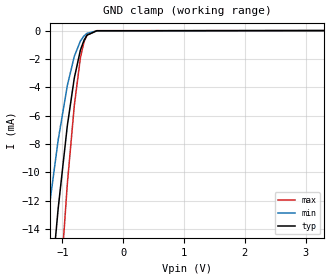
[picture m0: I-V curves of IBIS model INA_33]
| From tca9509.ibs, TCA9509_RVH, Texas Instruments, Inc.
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[Model]   INA_33
Model_type  Input
Vinl=0.15
Vinh=2.31
| variable   typ   min   max
C_comp   1.60pF   1.25pF   1.83pF
[Temperature Range]   40   100   -40
| Ambient temperature   25   85   -40
[Voltage range]   3.3   3   3.6
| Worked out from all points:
|   GND clamp passes 1 mA (typ) near -0.68 V on its own axis
[GND Clamp]
| INA_33
|   Voltage   I(typ)   I(min)   I(max)
-3.3V     -179.4mA   -131.1mA   -253.4mA
-1.42V    -30.67mA   -20.24mA   -47.89mA
-1.4V     -29.5mA    -19.42mA   -46.12mA
-1.22V    -19.63mA   -12.55mA   -31.1mA
-1.07V    -12.54mA   -7.714mA   -20.08mA
-920mV    -6.722mA   -3.883mA   -10.84mA
-805mV    -3.354mA   -1.825mA   -5.303mA
-705mV    -1.39mA    -740.7uA   -1.939mA
-645mV    -679uA     -375.8uA   -797.3uA
-595mV    -324.9uA   -196.1uA   -314.7uA
-435mV    -15.07uA   -14.81uA   -6.498uA
3.3V      311.6pA    1.532nA    54.55pA
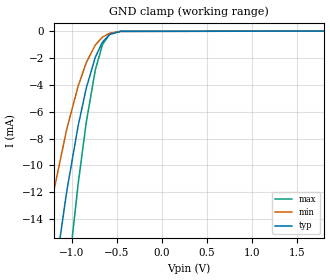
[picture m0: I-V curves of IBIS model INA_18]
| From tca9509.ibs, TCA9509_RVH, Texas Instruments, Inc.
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[Model]   INA_18
Model_type  Input
Vinl=0.15
Vinh=1.26
| variable   typ   min   max
C_comp   1.61pF   1.15pF   1.86pF
[Temperature Range]   40   100   -40
| Ambient temperature   25   85   -40
[Voltage range]   1.8   1.65   1.95
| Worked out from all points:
|   GND clamp passes 1 mA (typ) near -0.68 V on its own axis
[GND Clamp]
| INA_18
|   Voltage   I(typ)   I(min)   I(max)
-1.8V     -55.53mA   -37.93mA   -84.39mA
-1.395V   -29.2mA    -19.21mA   -45.68mA
-1.215V   -19.37mA   -12.38mA   -30.7mA
-1.065V   -12.32mA   -7.569mA   -19.74mA
-1.05V    -11.68mA   -7.139mA   -18.73mA
-930mV    -7.063mA   -4.101mA   -11.39mA
-840mV    -4.263mA   -2.36mA    -6.822mA
-740mV    -1.966mA   -1.047mA   -2.926mA
-660mV    -825.4uA   -449.9uA   -1.019mA
-580mV    -253.7uA   -159uA     -230.8uA
-460mV    -25.6uA    -23.29uA   -12.99uA
1.8V      196.2pA    1.052nA    29.84pA
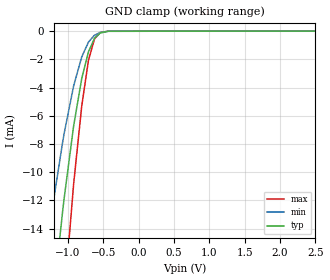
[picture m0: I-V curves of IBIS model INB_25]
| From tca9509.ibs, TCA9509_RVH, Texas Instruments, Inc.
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[Model]   INB_25
Model_type  Input
Vinl=0.15
Vinh=1.75
| variable   typ   min   max
C_comp   1.62pF   1.21pF   1.89pF
[Temperature Range]   40   100   -40
| Ambient temperature   25   85   -40
[Voltage range]   2.5   2.3   2.7
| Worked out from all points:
|   GND clamp passes 1 mA (typ) near -0.68 V on its own axis
[GND Clamp]
| INB_25
|   Voltage   I(typ)   I(min)   I(max)
-2.5V     -109.9mA   -78.03mA   -160.4mA
-1.405V   -29.79mA   -19.62mA   -46.56mA
-1.21V    -19.12mA   -12.2mA    -30.31mA
-1.075V   -12.75mA   -7.861mA   -20.42mA
-1.055V   -11.89mA   -7.281mA   -19.07mA
-920mV    -6.722mA   -3.883mA   -10.84mA
-805mV    -3.354mA   -1.825mA   -5.303mA
-710mV    -1.465mA   -779.9uA   -2.066mA
-625mV    -513.9uA   -292.4uA   -560.9uA
-545mV    -136.8uA   -94.94uA   -106.9uA
-430mV    -13.52uA   -13.5uA    -5.631uA
2.5V      247.4pA    1.266nA    41.34pA
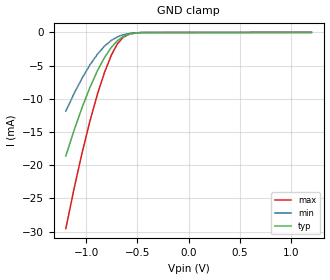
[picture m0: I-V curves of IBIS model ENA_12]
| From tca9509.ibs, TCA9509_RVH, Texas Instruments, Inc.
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[Model]   ENA_12
Model_type  Input
Vinl=0.15
Vinh=0.84
| variable   typ   min   max
C_comp   1.62pF   1.12pF   1.86pF
[Temperature Range]   40   100   -40
| Ambient temperature   25   85   -40
[Voltage range]   1.2   1.1   1.3
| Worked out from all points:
|   GND clamp passes 1 mA (typ) near -0.68 V on its own axis
[GND Clamp]
| ENA_12
|   Voltage   I(typ)   I(min)   I(max)
-1.2V     -18.61mA   -11.86mA   -29.54mA
-1.12V    -14.77mA   -9.228mA   -23.57mA
-1.04V    -11.26mA   -6.859mA   -18.07mA
-965mV    -8.314mA   -4.909mA   -13.39mA
-890mV    -5.741mA   -3.265mA   -9.247mA
-820mV    -3.73mA    -2.044mA   -5.935mA
-755mV    -2.25mA    -1.202mA   -3.417mA
-695mV    -1.248mA   -666.5uA   -1.7mA
-640mV    -634.6uA   -353.3uA   -732.1uA
-570mV    -213.8uA   -137.7uA   -186.4uA
-465mV    -28.41uA   -25.44uA   -14.85uA
1.2V      155.6pA    881.8pA    20.05pA
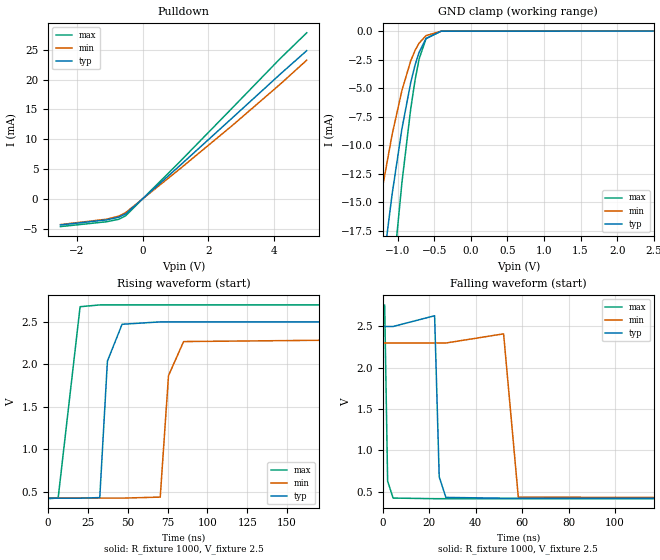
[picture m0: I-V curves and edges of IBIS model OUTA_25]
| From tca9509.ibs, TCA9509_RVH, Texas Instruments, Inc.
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[Model]   OUTA_25
Model_type  Open_drain
Enable   Active-High
Vref =   2.5
Rref =   1350
Cref =   50p
Vmeas =   1.25
| variable   typ   min   max
C_comp   2.30pF   1.66pF   2.63pF
| C_pulldown   1.52pF   1.14pF   1.79pF
| C_tri-state   2.30pF   1.66pF   2.63pF
[Temperature Range]   40   100   -40
| Ambient temperature   25   85   -40
[Voltage range]   2.5   2.3   2.7
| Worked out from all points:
|   slope of the pulldown table from 0 to 0.375 V, typ, clamps not added: 203 ohm
|   GND clamp passes 1 mA (typ) near -0.64 V on its own axis
|   rising waveform, R_fixture 1000, V_fixture 2.5: 20-80 % time 4.21ns typ, 4.62ns min, 3.89ns max; typ from 0.421 V to 2.5 V
|   falling waveform, R_fixture 1000, V_fixture 2.5: 20-80 % time 1.05ns typ, 1.56ns min, 682ps max; typ from 2.5 V to 0.421 V
[GND Clamp]
| OUTA_25
|   Voltage   I(typ)   I(min)   I(max)
-2.5V     -116.5mA   -83.67mA   -168.1mA
-1.425V   -33.77mA   -22.73mA   -51.61mA
-1.41V    -32.83mA   -22.07mA   -50.22mA
-1.225V   -21.99mA   -14.42mA   -33.96mA
-1.075V   -14.36mA   -9.116mA   -22.29mA
-940mV    -8.582mA   -5.209mA   -13.3mA
-820mV    -4.53mA    -2.622mA   -6.844mA
-760mV    -2.975mA   -1.694mA   -4.287mA
-705mV    -1.863mA   -1.062mA   -2.452mA
-610mV    -653.2uA   -398.9uA   -659.5uA
-405mV    -18.62uA   -19.65uA   -6.563uA
2.5V      643.1pA    3.147nA    138.3pA
[Pulldown]
| OUTA_25
|   Voltage   I(typ)   I(min)   I(max)
-2.5V     -4.294mA   -4.237mA   -4.572mA
-1.085V   -3.445mA   -3.33mA    -3.755mA
-720mV    -2.99mA    -2.815mA   -3.343mA
-515mV    -2.46mA    -2.232mA   -2.772mA
1.13V     5.587mA    5.039mA    6.233mA
2.73V     13.57mA    12.3mA     15.23mA
4.19V     20.88mA    19.21mA    23.49mA
5V        24.82mA    23.23mA    27.8mA
[Ramp]
| OUTA_25
| variable   typ   min   max
dV/dt_r   1.25/4.20E-09   1.13/4.60E-09   1.37/3.88E-09
dV/dt_f   1.32/1.11E-09   1.19/1.66E-09   1.46/7.19E-10
R_load = 1000
[Rising Waveform]
| OUTA_25
R_fixture =   1000
C_fixture =   0
L_fixture =   0
V_fixture =   2.5
V_fixture_min = 2.3
V_fixture_max = 2.7
|   Time   V(typ)   V(min)   V(max)
0s        421mV      421.9mV    415.3mV
6.277ns   421mV      421.9mV    423.7mV
20.04ns   421mV      421.9mV    2.679V
32.39ns   428.4mV    421.9mV    2.7V
37.19ns   2.038V     421.9mV    2.7V
46.4ns    2.472V     421.9mV    2.7V
70.34ns   2.5V       434.1mV    2.7V
75.53ns   2.5V       1.866V     2.7V
85ns      2.5V       2.268V     2.7V
266.4ns   2.5V       2.3V       2.7V
[Falling Waveform]
| OUTA_25
R_fixture =   1000
C_fixture =   0
L_fixture =   0
V_fixture =   2.5
V_fixture_min = 2.3
V_fixture_max = 2.7
|   Time   V(typ)   V(min)   V(max)
0s        2.5V       2.3V       2.7V
773ps     2.5V       2.3V       2.761V
2.053ns   2.5V       2.3V       627mV
4.421ns   2.5V       2.3V       422.9mV
22.28ns   2.63V      2.3V       415.5mV
24.26ns   678.8mV    2.3V       415.5mV
27.14ns   431mV      2.3V       415.5mV
51.98ns   421.1mV    2.411V     415.4mV
58.31ns   421.1mV    434.1mV    415.4mV
266.4ns   421mV      421.9mV    415.4mV
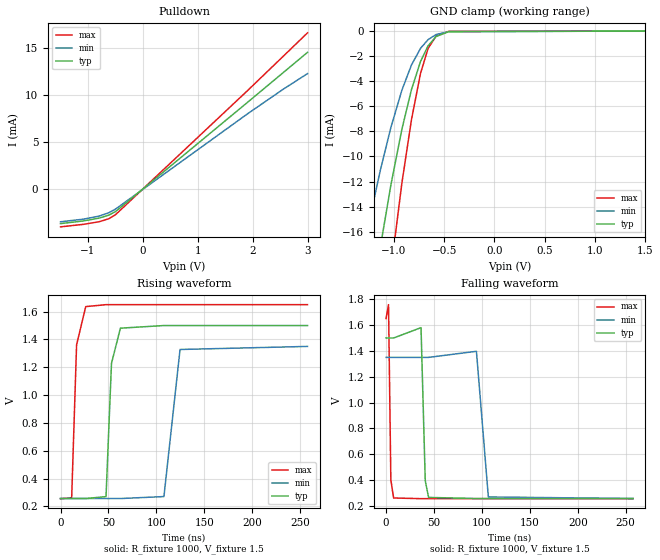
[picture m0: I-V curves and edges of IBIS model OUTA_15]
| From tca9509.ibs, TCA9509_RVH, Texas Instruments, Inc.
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[Model]   OUTA_15
Model_type  Open_drain
Enable   Active-High
Vref =   1.5
Rref =   1350
Cref =   50p
Vmeas =   0.75
| variable   typ   min   max
C_comp   2.24pF   1.55pF   2.59pF
| C_pulldown   1.49pF   1.04pF   1.72pF
| C_tri-state   2.24pF   1.55pF   2.59pF
[Temperature Range]   40   100   -40
| Ambient temperature   25   85   -40
[Voltage range]   1.5   1.35   1.65
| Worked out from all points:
|   slope of the pulldown table from 0 to 0.225 V, typ, clamps not added: 207 ohm
|   GND clamp passes 1 mA (typ) near -0.64 V on its own axis
|   rising waveform, R_fixture 1000, V_fixture 1.5: 20-80 % time 4.8ns typ, 5.8ns min, 4.18ns max; typ from 0.257 V to 1.5 V
|   falling waveform, R_fixture 1000, V_fixture 1.5: 20-80 % time 2.31ns typ, 4.22ns min, 1.3ns max; typ from 1.5 V to 0.257 V
[GND Clamp]
| OUTA_15
|   Voltage   I(typ)   I(min)   I(max)
-1.5V     -38.59mA   -26.17mA   -58.73mA
-1.37V    -30.37mA   -20.32mA   -46.55mA
-1.25V    -23.37mA   -15.38mA   -36.05mA
-1.135V   -17.27mA   -11.13mA   -26.77mA
-1.03V    -12.31mA   -7.711mA   -19.12mA
-920mV    -7.829mA   -4.714mA   -12.12mA
-825mV    -4.675mA   -2.71mA    -7.079mA
-735mV    -2.432mA   -1.382mA   -3.384mA
-660mV    -1.183mA   -687.3uA   -1.393mA
-580mV    -435.1uA   -278.8uA   -396.9uA
-455mV    -52.59uA   -46.76uA   -26.73uA
1.5V      453pA      2.396nA    83.27pA
[Pulldown]
| OUTA_15
|   Voltage   I(typ)   I(min)   I(max)
-1.5V     -3.612mA   -3.422mA   -3.956mA
-1.08V    -3.33mA    -3.14mA    -3.689mA
-795mV    -3.03mA    -2.816mA   -3.412mA
-620mV    -2.716mA   -2.462mA   -3.097mA
-495mV    -2.332mA   -2.067mA   -2.655mA
1.905V    9.201mA    7.988mA    10.44mA
2.55V     12.32mA    10.57mA    14.04mA
3V        14.5mA     12.25mA    16.56mA
[Ramp]
| OUTA_15
| variable   typ   min   max
dV/dt_r   0.75/4.78E-09   0.66/5.78E-09   0.84/4.17E-09
dV/dt_f   0.80/2.49E-09   0.69/4.44E-09   0.91/1.42E-09
R_load = 1000
[Rising Waveform]
| OUTA_15
R_fixture =   1000
C_fixture =   0
L_fixture =   0
V_fixture =   1.5
V_fixture_min = 1.35
V_fixture_max = 1.65
|   Time   V(typ)   V(min)   V(max)
0s        257.3mV    257.1mV    256.1mV
11.65ns   257.3mV    257.1mV    262.1mV
16.77ns   257.3mV    257.1mV    1.361V
26.31ns   257.3mV    257.1mV    1.636V
47.49ns   270.8mV    257.1mV    1.65V
53.19ns   1.228V     257.1mV    1.65V
62.47ns   1.481V     257.1mV    1.65V
107.9ns   1.5V       271.3mV    1.65V
124.7ns   1.5V       1.328V     1.65V
257.7ns   1.5V       1.35V      1.65V
[Falling Waveform]
| OUTA_15
R_fixture =   1000
C_fixture =   0
L_fixture =   0
V_fixture =   1.5
V_fixture_min = 1.35
V_fixture_max = 1.65
|   Time   V(typ)   V(min)   V(max)
0s        1.5V       1.35V      1.65V
2.565ns   1.5V       1.35V      1.758V
4.997ns   1.5V       1.35V      401mV
7.877ns   1.5V       1.35V      261.5mV
36.48ns   1.58V      1.35V      256.2mV
40.9ns    394.8mV    1.35V      256.2mV
44.36ns   265.8mV    1.35V      256.2mV
94.28ns   257.3mV    1.397V     256.2mV
106.7ns   257.3mV    269.6mV    256.2mV
257.7ns   257.3mV    257.1mV    256.1mV
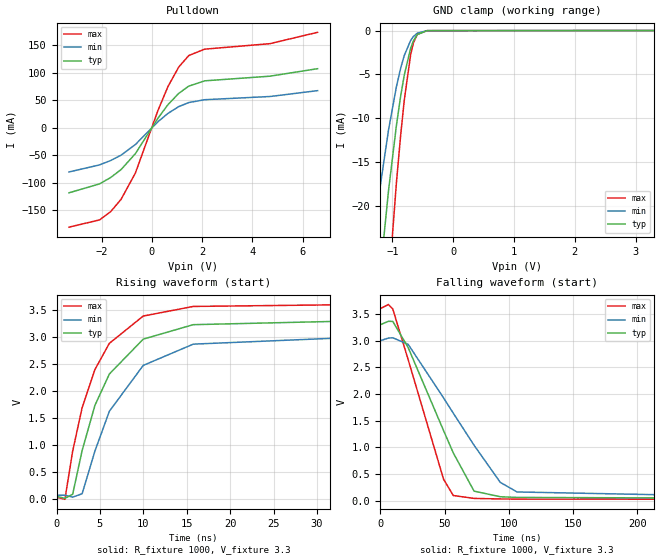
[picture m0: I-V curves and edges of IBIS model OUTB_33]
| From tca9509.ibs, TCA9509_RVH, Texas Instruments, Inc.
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[Model]   OUTB_33
Model_type  Open_drain
Enable   Active-High
Vref =   3.3
Rref =   1350
Cref =   50p
Vmeas =   1.65
| variable   typ   min   max
C_comp   2.88pF   2.03pF   3.27pF
| C_pulldown   2.79pF   2.11pF   3.88pF
| C_tri-state   2.88pF   2.03pF   3.27pF
[Temperature Range]   40   100   -40
| Ambient temperature   25   85   -40
[Voltage range]   3.3   3   3.6
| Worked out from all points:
|   slope of the pulldown table from 0 to 0.495 V, typ, clamps not added: 14.8 ohm
|   GND clamp passes 1 mA (typ) near -0.64 V on its own axis
|   rising waveform, R_fixture 1000, V_fixture 3.3: 20-80 % time 4.93ns typ, 5.55ns min, 4.4ns max; typ from 0.044 V to 3.3 V
|   falling waveform, R_fixture 1000, V_fixture 3.3: 20-80 % time 34.8ns typ, 47.4ns min, 26.1ns max; typ from 3.3 V to 0.044 V
[GND Clamp]
| OUTB_33
|   Voltage   I(typ)   I(min)   I(max)
-3.3V     -255.6mA   -185.6mA   -366mA
-1.415V   -44.45mA   -29.41mA   -69.66mA
-1.23V    -29.68mA   -19.14mA   -47.05mA
-1.065V   -18.31mA   -11.37mA   -29.3mA
-935mV    -10.85mA   -6.424mA   -17.41mA
-865mV    -7.504mA   -4.308mA   -11.97mA
-805mV    -5.083mA   -2.848mA   -7.943mA
-700mV    -2.008mA   -1.123mA   -2.73mA
-655mV    -1.177mA   -683.2uA   -1.416mA
-590mV    -452uA     -295.1uA   -428.3uA
-430mV    -20.32uA   -20.58uA   -8.486uA
3.3V      610.5pA    2.442nA    227pA
[Pulldown]
| OUTB_33
|   Voltage   I(typ)   I(min)   I(max)
-3.3V     -118.1mA   -80.27mA   -180.4mA
-2.085V   -101.9mA   -67.44mA   -167.3mA
-1.64V    -90.38mA   -59.49mA   -152.3mA
-1.225V   -75.93mA   -49.79mA   -129.9mA
-655mV    -47.02mA   -30.42mA   -82.22mA
245mV     17.44mA    10.94mA    31.41mA
640mV     41.74mA    25.98mA    74.55mA
1.07V     62.35mA    38.33mA    110.1mA
1.47V     75.55mA    45.73mA    131mA
2.11V     85.18mA    50.92mA    142.7mA
4.7V      93.58mA    56.69mA    152.6mA
6.6V      107.2mA    67.34mA    173.2mA
[Ramp]
| OUTB_33
| variable   typ   min   max
dV/dt_r   1.98/4.92E-09   1.78/5.54E-09   2.19/4.39E-09
dV/dt_f   1.99/3.55E-08   1.79/4.82E-08   2.19/2.67E-08
R_load = 1000
[Rising Waveform]
| OUTB_33
R_fixture =   1000
C_fixture =   0
L_fixture =   0
V_fixture =   3.3
V_fixture_min = 3
V_fixture_max = 3.6
|   Time   V(typ)   V(min)   V(max)
0s        43.95mV    63.27mV    26.59mV
965ps     5.153mV    63.31mV    -12.32mV
1.861ns   82.67mV    27.98mV    882.2mV
2.949ns   892.6mV    91.66mV    1.687V
4.421ns   1.729V     882mV      2.394V
6.085ns   2.311V     1.62V      2.88V
9.989ns   2.958V     2.471V     3.386V
15.75ns   3.226V     2.865V     3.564V
35.27ns   3.299V     2.997V     3.6V
317.4ns   3.3V       3V         3.6V
[Falling Waveform]
| OUTB_33
R_fixture =   1000
C_fixture =   0
L_fixture =   0
V_fixture =   3.3
V_fixture_min = 3
V_fixture_max = 3.6
|   Time   V(typ)   V(min)   V(max)
0s        3.3V       3V         3.6V
6.341ns   3.364V     3.05V      3.679V
9.733ns   3.362V     3.055V     3.595V
21.7ns    2.872V     2.932V     2.645V
49.22ns   1.317V     1.929V     405.2mV
56.77ns   899mV      1.643V     98.53mV
72.97ns   180.5mV    1.041V     43.92mV
93.38ns   75.31mV    344.4mV    33.63mV
106.4ns   62.57mV    164.9mV    31.15mV
317.4ns   44.17mV    64.3mV     26.62mV
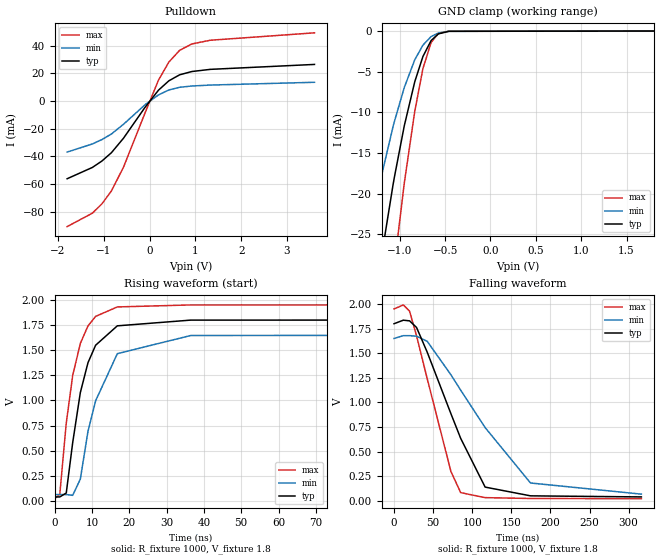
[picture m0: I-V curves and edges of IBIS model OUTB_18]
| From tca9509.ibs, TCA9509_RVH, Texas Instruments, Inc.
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[Model]   OUTB_18
Model_type  Open_drain
Enable   Active-High
Vref =   1.8
Rref =   1350
Cref =   50p
Vmeas =   0.9
| variable   typ   min   max
C_comp   2.74pF   1.72pF   3.20pF
| C_pulldown   3.00pF   2.13pF   4.25pF
| C_tri-state   2.74pF   1.72pF   3.20pF
[Temperature Range]   40   100   -40
| Ambient temperature   25   85   -40
[Voltage range]   1.8   1.65   1.95
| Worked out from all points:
|   slope of the pulldown table from 0 to 0.27 V, typ, clamps not added: 26 ohm
|   GND clamp passes 1 mA (typ) near -0.64 V on its own axis
|   rising waveform, R_fixture 1000, V_fixture 1.8: 20-80 % time 5.48ns typ, 6.83ns min, 4.64ns max; typ from 0.04 V to 1.8 V
|   falling waveform, R_fixture 1000, V_fixture 1.8: 20-80 % time 52.4ns typ, 80.1ns min, 36.7ns max; typ from 1.8 V to 0.041 V
[GND Clamp]
| OUTB_18
|   Voltage   I(typ)   I(min)   I(max)
-1.8V     -80.42mA   -54.92mA   -123.1mA
-1.415V   -44.45mA   -29.41mA   -69.66mA
-1.23V    -29.68mA   -19.14mA   -47.05mA
-1.075V   -18.95mA   -11.79mA   -30.3mA
-1.06V    -18mA      -11.15mA   -28.81mA
-950mV    -11.63mA   -6.931mA   -18.67mA
-835mV    -6.238mA   -3.535mA   -9.876mA
-745mV    -3.133mA   -1.736mA   -4.625mA
-655mV    -1.177mA   -683.2uA   -1.416mA
-575mV    -351.2uA   -238uA     -312.7uA
-460mV    -38.47uA   -35.77uA   -19.56uA
1.8V      372.7pA    1.658nA    124pA
[Pulldown]
| OUTB_18
|   Voltage   I(typ)   I(min)   I(max)
-1.8V     -56.21mA   -36.94mA   -90.83mA
-1.25V    -48.06mA   -31.06mA   -81.14mA
-1.04V    -43.38mA   -27.88mA   -74.36mA
-835mV    -37.44mA   -23.89mA   -65.12mA
-570mV    -26.9mA    -16.82mA   -47.87mA
-95mV     -4.354mA   -2.564mA   -8.249mA
195mV     7.876mA    4.45mA     15.17mA
420mV     14.6mA     7.975mA    28.14mA
655mV     18.95mA    9.919mA    36.65mA
920mV     21.32mA    10.85mA    41.26mA
1.325V    22.9mA     11.54mA    43.96mA
3.6V      26.47mA    13.55mA    49.33mA
[Ramp]
| OUTB_18
| variable   typ   min   max
dV/dt_r   1.06/5.48E-09   0.96/6.83E-09   1.17/4.64E-09
dV/dt_f   1.08/5.34E-08   0.97/8.15E-08   1.18/3.75E-08
R_load = 1000
[Rising Waveform]
| OUTB_18
R_fixture =   1000
C_fixture =   0
L_fixture =   0
V_fixture =   1.8
V_fixture_min = 1.65
V_fixture_max = 1.95
|   Time   V(typ)   V(min)   V(max)
0s        39.82mV    63.43mV    22.4mV
1.349ns   40.04mV    63.43mV    67.76mV
3.077ns   78.8mV     63.54mV    774.1mV
4.805ns   580.6mV    55.76mV    1.248V
6.853ns   1.078V     217.7mV    1.567V
8.901ns   1.375V     692.3mV    1.741V
10.95ns   1.549V     996.3mV    1.836V
16.77ns   1.742V     1.465V     1.93V
36.48ns   1.799V     1.646V     1.95V
316.3ns   1.8V       1.65V      1.95V
[Falling Waveform]
| OUTB_18
R_fixture =   1000
C_fixture =   0
L_fixture =   0
V_fixture =   1.8
V_fixture_min = 1.65
V_fixture_max = 1.95
|   Time   V(typ)   V(min)   V(max)
0s        1.8V       1.65V      1.95V
11.91ns   1.836V     1.679V     1.991V
19.91ns   1.829V     1.679V     1.927V
28.8ns    1.762V     1.673V     1.677V
42.5ns    1.51V      1.621V     1.24V
72.77ns   885.7mV    1.281V     299mV
85.25ns   635.3mV    1.125V     84.19mV
116.5ns   140.3mV    745mV      33.28mV
174.5ns   51.47mV    182.1mV    24.51mV
316.3ns   40.52mV    68.74mV    22.49mV
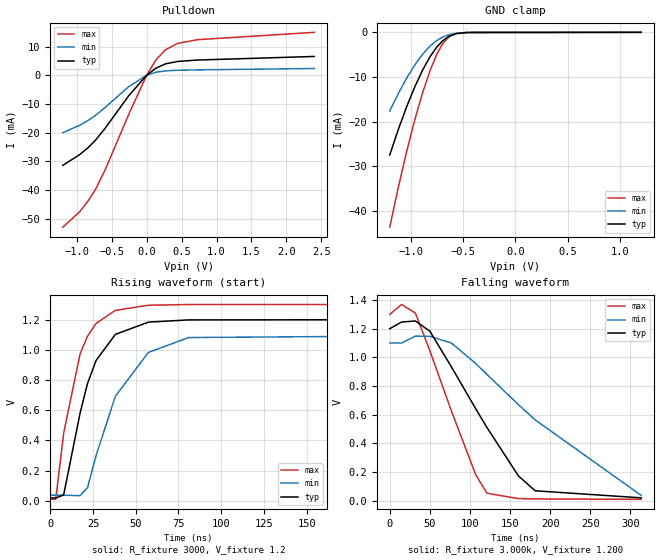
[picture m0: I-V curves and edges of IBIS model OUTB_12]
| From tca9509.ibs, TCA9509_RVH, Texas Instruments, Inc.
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[Model]   OUTB_12
Model_type  Open_drain
Enable   Active-High
Vref =   1.2
Rref =   1350
Cref =   50p
Vmeas =   0.6
| variable   typ   min   max
C_comp   2.44pF   1.65pF   3.03pF
| C_pulldown   3.01pF   2.05pF   4.31pF
| C_tri-state   2.44pF   1.65pF   3.03pF
[Temperature Range]   40   100   -40
| Ambient temperature   25   85   -40
[Voltage range]   1.2   1.1   1.3
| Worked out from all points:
|   slope of the pulldown table from 0 to 0.18 V, typ, clamps not added: 58.1 ohm
|   GND clamp passes 1 mA (typ) near -0.64 V on its own axis
|   rising waveform, R_fixture 3000, V_fixture 1.2: 20-80 % time 16.4ns typ, 23.7ns min, 13.9ns max; typ from 0.018 V to 1.2 V
|   falling waveform, R_fixture 3.000k, V_fixture 1.200: 20-80 % time 76.3ns typ, 129ns min, 50.6ns max; typ from 1.2 V to 0.019 V
[GND Clamp]
| OUTB_12
|   Voltage   I(typ)   I(min)   I(max)
-1.2V     -27.47mA   -17.62mA   -43.63mA
-1.115V   -21.55mA   -13.56mA   -34.4mA
-1.035V   -16.46mA   -10.12mA   -26.37mA
-960mV    -12.17mA   -7.279mA   -19.53mA
-885mV    -8.406mA   -4.869mA   -13.45mA
-815mV    -5.455mA   -3.068mA   -8.569mA
-750mV    -3.277mA   -1.815mA   -4.87mA
-695mV    -1.901mA   -1.066mA   -2.555mA
-635mV    -898.1uA   -536uA     -1.011mA
-565mV    -295.1uA   -205.3uA   -251.9uA
-460mV    -38.47uA   -35.77uA   -19.56uA
1.2V      285.9pA    1.377nA    82.81pA
[Pulldown]
| OUTB_12
|   Voltage   I(typ)   I(min)   I(max)
-1.2V     -31.34mA   -20mA      -52.86mA
-960mV    -27.63mA   -17.41mA   -47.52mA
-840mV    -25.24mA   -15.75mA   -43.8mA
-735mV    -22.67mA   -14.01mA   -39.83mA
-595mV    -18.46mA   -11.2mA    -32.97mA
-255mV    -7.065mA   -3.938mA   -13.51mA
0V        0A         0A         0A
130mV     2.428mA    1.035mA    5.274mA
270mV     3.976mA    1.535mA    8.894mA
445mV     4.806mA    1.735mA    11.09mA
725mV     5.294mA    1.871mA    12.37mA
2.4V      6.543mA    2.355mA    14.94mA
[Ramp]
| OUTB_12
| variable   typ   min   max
dV/dt_r   0.71/1.64E-08   0.64/2.37E-08   0.79/1.39E-08
dV/dt_f   0.74/7.96E-08   0.63/1.34E-07   0.82/5.32E-08
R_load = 3000
[Rising Waveform]
| OUTB_12
R_fixture =   3000
C_fixture =   0
L_fixture =   0
V_fixture =   1.2
V_fixture_min = 1.1
V_fixture_max = 1.3
|   Time   V(typ)   V(min)   V(max)
0s        17.9mV     36.45mV    9.051mV
3.205ns   17.94mV    36.45mV    10mV
7.813ns   37.79mV    36.45mV    445.5mV
17.41ns   578.8mV    33.38mV    972.4mV
21.77ns   776.4mV    85.44mV    1.09V
26.82ns   929.9mV    300mV      1.175V
38.08ns   1.102V     692.1mV    1.261V
57.35ns   1.183V     981.9mV    1.295V
80.9ns    1.198V     1.081V     1.3V
313.5ns   1.2V       1.1V       1.3V
[Falling Waveform]
R_fixture = 3.000k
V_fixture = 1.200
V_fixture_min = 1.100
V_fixture_max = 1.300
C_fixture = 0.000
L_fixture = 0.000
|  time   V(typ)   V(min)   V(max)
0s        1.2V       1.1V       1.3V
14.85ns   1.247V     1.1V       1.369V
32.01ns   1.254V     1.148V     1.309V
49.99ns   1.183V     1.147V     1.047V
76.93ns   933.5mV    1.1V       625.5mV
107.3ns   640.6mV    957.1mV    179.7mV
121.2ns   510.5mV    881.1mV    51.93mV
160.6ns   171.8mV    669.5mV    14.21mV
181.3ns   68.92mV    563.9mV    11.79mV
313.5ns   19.48mV    36.56mV    9.187mV
